VERSION 5.7 ;
  NOWIREEXTENSIONATPIN ON ;
  DIVIDERCHAR "/" ;
  BUSBITCHARS "[]" ;
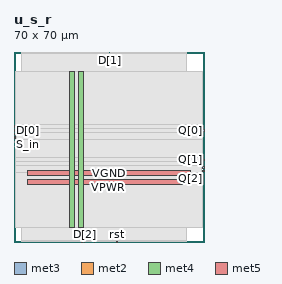
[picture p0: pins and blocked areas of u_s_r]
MACRO u_s_r
  CLASS BLOCK ;
  FOREIGN u_s_r ;
  ORIGIN 0.000 0.000 ;
  SIZE 70.000 BY 70.000 ;
  PIN D[0]
    DIRECTION INPUT ;
    USE SIGNAL ;
    ANTENNAGATEAREA 0.213000 ;
    PORT
      LAYER met3 ;
        RECT 0.000 40.840 0.600 41.440 ;
    END
  END D[0]
  PIN D[1]
    DIRECTION INPUT ;
    USE SIGNAL ;
    ANTENNAGATEAREA 0.213000 ;
    PORT
      LAYER met2 ;
        RECT 35.050 69.720 35.330 70.000 ;
    END
  END D[1]
  PIN D[2]
    DIRECTION INPUT ;
    USE SIGNAL ;
    ANTENNAGATEAREA 0.213000 ;
    PORT
      LAYER met2 ;
        RECT 25.850 0.000 26.130 0.280 ;
    END
  END D[2]
  PIN D[3]
    DIRECTION INPUT ;
    USE SIGNAL ;
    ANTENNAGATEAREA 0.213000 ;
    PORT
      LAYER met2 ;
        RECT 24.930 0.000 25.210 0.280 ;
    END
  END D[3]
  PIN Q[0]
    DIRECTION OUTPUT ;
    USE SIGNAL ;
    ANTENNADIFFAREA 0.702900 ;
    PORT
      LAYER met3 ;
        RECT 69.400 40.840 70.000 41.440 ;
    END
  END Q[0]
  PIN Q[1]
    DIRECTION OUTPUT ;
    USE SIGNAL ;
    ANTENNADIFFAREA 0.702900 ;
    PORT
      LAYER met3 ;
        RECT 69.400 29.960 70.000 30.560 ;
    END
  END Q[1]
  PIN Q[2]
    DIRECTION OUTPUT ;
    USE SIGNAL ;
    ANTENNADIFFAREA 0.702900 ;
    PORT
      LAYER met3 ;
        RECT 69.400 25.880 70.000 26.480 ;
    END
  END Q[2]
  PIN Q[3]
    DIRECTION OUTPUT ;
    USE SIGNAL ;
    ANTENNADIFFAREA 0.702900 ;
    PORT
      LAYER met2 ;
        RECT 29.530 0.000 29.810 0.280 ;
    END
  END Q[3]
  PIN S_in
    DIRECTION INPUT ;
    USE SIGNAL ;
    ANTENNAGATEAREA 0.213000 ;
    PORT
      LAYER met3 ;
        RECT 0.000 38.120 0.600 38.720 ;
    END
  END S_in
  PIN VGND
    DIRECTION INOUT ;
    USE GROUND ;
    PORT
      LAYER met4 ;
        RECT 23.880 5.200 25.480 62.800 ;
    END
    PORT
      LAYER met5 ;
        RECT 5.060 24.590 64.860 26.190 ;
    END
  END VGND
  PIN VPWR
    DIRECTION INOUT ;
    USE POWER ;
    PORT
      LAYER met4 ;
        RECT 20.580 5.200 22.180 62.800 ;
    END
    PORT
      LAYER met5 ;
        RECT 5.060 21.290 64.860 22.890 ;
    END
  END VPWR
  PIN clk
    DIRECTION INPUT ;
    USE SIGNAL ;
    ANTENNAGATEAREA 0.852000 ;
    PORT
      LAYER met3 ;
        RECT 69.400 27.240 70.000 27.840 ;
    END
  END clk
  PIN mode[0]
    DIRECTION INPUT ;
    USE SIGNAL ;
    ANTENNAGATEAREA 0.213000 ;
    PORT
      LAYER met3 ;
        RECT 0.000 39.480 0.600 40.080 ;
    END
  END mode[0]
  PIN mode[1]
    DIRECTION INPUT ;
    USE SIGNAL ;
    ANTENNAGATEAREA 0.213000 ;
    PORT
      LAYER met3 ;
        RECT 0.000 42.200 0.600 42.800 ;
    END
  END mode[1]
  PIN rst
    DIRECTION INPUT ;
    USE SIGNAL ;
    ANTENNAGATEAREA 0.213000 ;
    PORT
      LAYER met2 ;
        RECT 37.810 0.000 38.090 0.280 ;
    END
  END rst
  OBS
      LAYER nwell ;
        RECT 4.870 5.355 65.050 62.750 ;
      LAYER li1 ;
        RECT 5.060 5.355 64.860 62.645 ;
      LAYER met1 ;
        RECT 2.830 5.200 64.860 62.800 ;
      LAYER met2 ;
        RECT 2.850 69.440 34.770 69.720 ;
        RECT 35.610 69.440 63.390 69.720 ;
        RECT 2.850 0.560 63.390 69.440 ;
        RECT 2.850 0.070 24.650 0.560 ;
        RECT 25.490 0.070 25.570 0.560 ;
        RECT 26.410 0.070 29.250 0.560 ;
        RECT 30.090 0.070 37.530 0.560 ;
        RECT 38.370 0.070 63.390 0.560 ;
      LAYER met3 ;
        RECT 0.600 43.200 69.400 62.725 ;
        RECT 1.000 41.840 69.400 43.200 ;
        RECT 1.000 40.440 69.000 41.840 ;
        RECT 1.000 37.720 69.400 40.440 ;
        RECT 0.600 30.960 69.400 37.720 ;
        RECT 0.600 29.560 69.000 30.960 ;
        RECT 0.600 28.240 69.400 29.560 ;
        RECT 0.600 25.480 69.000 28.240 ;
        RECT 0.600 5.275 69.400 25.480 ;
  END
END u_s_r
END LIBRARY

